VERSION 5.7 ;
  NOWIREEXTENSIONATPIN ON ;
  DIVIDERCHAR "/" ;
  BUSBITCHARS "[]" ;
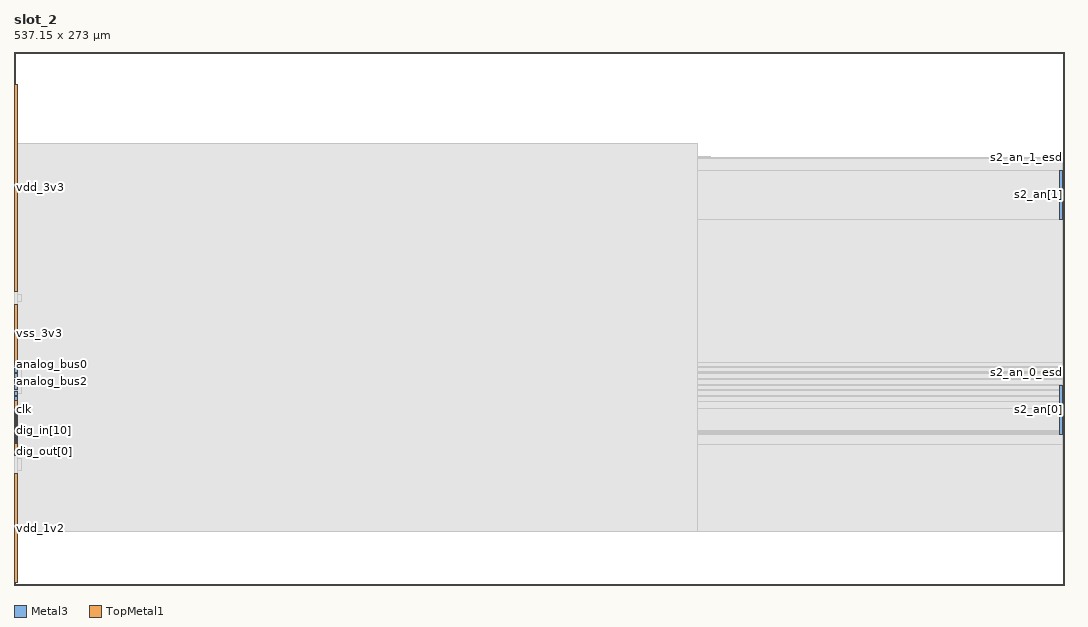
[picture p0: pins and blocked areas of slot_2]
MACRO slot_2
  CLASS BLOCK ;
  FOREIGN slot_2 ;
  ORIGIN 0.000 -0.010 ;
  SIZE 537.150 BY 273.000 ;
  PIN s2_an[0]
    ANTENNADIFFAREA 12.240000 ;
    PORT
      LAYER Metal3 ;
        RECT 535.050 77.160 536.440 101.930 ;
    END
  END s2_an[0]
  PIN s2_an[1]
    ANTENNADIFFAREA 12.240000 ;
    PORT
      LAYER Metal3 ;
        RECT 535.050 187.160 536.440 211.930 ;
    END
  END s2_an[1]
  PIN s2_an_0_esd
    PORT
      LAYER Metal3 ;
        RECT 535.150 108.415 537.150 108.905 ;
    END
  END s2_an_0_esd
  PIN s2_an_1_esd
    PORT
      LAYER Metal3 ;
        RECT 535.150 218.415 537.150 218.905 ;
    END
  END s2_an_1_esd
  PIN vbias
    PORT
      LAYER Metal3 ;
        RECT 0.000 94.215 2.000 96.215 ;
    END
  END vbias
  PIN dig_in[23]
    PORT
      LAYER Metal3 ;
        RECT 0.000 88.470 2.000 88.690 ;
    END
  END dig_in[23]
  PIN dig_in[22]
    PORT
      LAYER Metal3 ;
        RECT 0.000 88.030 2.000 88.250 ;
    END
  END dig_in[22]
  PIN dig_in[21]
    PORT
      LAYER Metal3 ;
        RECT 0.000 87.590 2.000 87.810 ;
    END
  END dig_in[21]
  PIN dig_in[20]
    PORT
      LAYER Metal3 ;
        RECT 0.000 87.150 2.000 87.370 ;
    END
  END dig_in[20]
  PIN dig_in[19]
    PORT
      LAYER Metal3 ;
        RECT 0.000 86.710 2.000 86.930 ;
    END
  END dig_in[19]
  PIN dig_in[18]
    PORT
      LAYER Metal3 ;
        RECT 0.000 86.270 2.000 86.490 ;
    END
  END dig_in[18]
  PIN dig_in[17]
    PORT
      LAYER Metal3 ;
        RECT 0.000 85.830 2.000 86.050 ;
    END
  END dig_in[17]
  PIN dig_in[16]
    PORT
      LAYER Metal3 ;
        RECT 0.000 85.390 2.000 85.610 ;
    END
  END dig_in[16]
  PIN dig_in[15]
    PORT
      LAYER Metal3 ;
        RECT 0.000 84.950 2.000 85.170 ;
    END
  END dig_in[15]
  PIN dig_in[14]
    PORT
      LAYER Metal3 ;
        RECT 0.000 84.510 2.000 84.730 ;
    END
  END dig_in[14]
  PIN dig_in[13]
    PORT
      LAYER Metal3 ;
        RECT 0.000 84.070 2.000 84.290 ;
    END
  END dig_in[13]
  PIN dig_in[12]
    PORT
      LAYER Metal3 ;
        RECT 0.000 83.630 2.000 83.850 ;
    END
  END dig_in[12]
  PIN dig_in[11]
    PORT
      LAYER Metal3 ;
        RECT 0.000 83.190 2.000 83.410 ;
    END
  END dig_in[11]
  PIN dig_in[10]
    PORT
      LAYER Metal3 ;
        RECT 0.000 82.750 2.000 82.970 ;
    END
  END dig_in[10]
  PIN dig_in[9]
    PORT
      LAYER Metal3 ;
        RECT 0.000 82.310 2.000 82.530 ;
    END
  END dig_in[9]
  PIN dig_in[8]
    PORT
      LAYER Metal3 ;
        RECT 0.000 81.870 2.000 82.090 ;
    END
  END dig_in[8]
  PIN dig_in[7]
    PORT
      LAYER Metal3 ;
        RECT 0.000 81.430 2.000 81.650 ;
    END
  END dig_in[7]
  PIN dig_in[6]
    PORT
      LAYER Metal3 ;
        RECT 0.000 80.990 2.000 81.210 ;
    END
  END dig_in[6]
  PIN dig_in[5]
    PORT
      LAYER Metal3 ;
        RECT 0.000 80.550 2.000 80.770 ;
    END
  END dig_in[5]
  PIN dig_in[4]
    PORT
      LAYER Metal3 ;
        RECT 0.000 80.110 2.000 80.330 ;
    END
  END dig_in[4]
  PIN dig_in[3]
    PORT
      LAYER Metal3 ;
        RECT 0.000 79.670 2.000 79.890 ;
    END
  END dig_in[3]
  PIN dig_in[2]
    PORT
      LAYER Metal3 ;
        RECT 0.000 79.230 2.000 79.450 ;
    END
  END dig_in[2]
  PIN dig_in[1]
    ANTENNAGATEAREA 0.260000 ;
    PORT
      LAYER Metal3 ;
        RECT 0.000 78.790 3.495 79.010 ;
    END
  END dig_in[1]
  PIN dig_in[0]
    ANTENNAGATEAREA 0.260000 ;
    PORT
      LAYER Metal3 ;
        RECT 0.000 78.350 4.085 78.570 ;
    END
  END dig_in[0]
  PIN dig_out[11]
    PORT
      LAYER Metal3 ;
        RECT 0.000 77.030 2.000 77.250 ;
    END
  END dig_out[11]
  PIN dig_out[10]
    PORT
      LAYER Metal3 ;
        RECT 0.000 76.590 2.000 76.810 ;
    END
  END dig_out[10]
  PIN dig_out[9]
    PORT
      LAYER Metal3 ;
        RECT 0.000 76.150 2.000 76.370 ;
    END
  END dig_out[9]
  PIN dig_out[8]
    PORT
      LAYER Metal3 ;
        RECT 0.000 75.710 2.000 75.930 ;
    END
  END dig_out[8]
  PIN dig_out[7]
    PORT
      LAYER Metal3 ;
        RECT 0.000 75.270 2.000 75.490 ;
    END
  END dig_out[7]
  PIN dig_out[6]
    PORT
      LAYER Metal3 ;
        RECT 0.000 74.830 2.000 75.050 ;
    END
  END dig_out[6]
  PIN dig_out[5]
    PORT
      LAYER Metal3 ;
        RECT 0.000 74.390 2.000 74.610 ;
    END
  END dig_out[5]
  PIN dig_out[4]
    PORT
      LAYER Metal3 ;
        RECT 0.000 73.950 2.000 74.170 ;
    END
  END dig_out[4]
  PIN dig_out[3]
    PORT
      LAYER Metal3 ;
        RECT 0.000 73.510 2.000 73.730 ;
    END
  END dig_out[3]
  PIN dig_out[2]
    PORT
      LAYER Metal3 ;
        RECT 0.000 73.070 2.000 73.290 ;
    END
  END dig_out[2]
  PIN dig_out[1]
    PORT
      LAYER Metal3 ;
        RECT 0.000 72.630 2.000 72.850 ;
    END
  END dig_out[1]
  PIN dig_out[0]
    PORT
      LAYER Metal3 ;
        RECT 0.000 72.190 2.000 72.410 ;
    END
  END dig_out[0]
  PIN ibias0
    PORT
      LAYER Metal3 ;
        RECT 0.000 97.155 2.000 99.155 ;
    END
  END ibias0
  PIN ibias1
    PORT
      LAYER Metal3 ;
        RECT 0.000 100.095 2.000 102.095 ;
    END
  END ibias1
  PIN analog_bus3
    PORT
      LAYER Metal3 ;
        RECT 0.000 103.035 2.000 105.035 ;
    END
  END analog_bus3
  PIN analog_bus2
    PORT
      LAYER Metal3 ;
        RECT 0.000 105.975 2.000 107.975 ;
    END
  END analog_bus2
  PIN analog_bus1
    PORT
      LAYER Metal3 ;
        RECT 0.000 108.915 2.000 110.915 ;
    END
  END analog_bus1
  PIN analog_bus0
    PORT
      LAYER Metal3 ;
        RECT 0.000 111.855 2.000 113.855 ;
    END
  END analog_bus0
  PIN enable
    PORT
      LAYER Metal3 ;
        RECT 0.000 89.360 2.000 89.580 ;
    END
  END enable
  PIN clk
    PORT
      LAYER Metal3 ;
        RECT 0.000 89.800 2.000 90.020 ;
    END
  END clk
  PIN reset
    PORT
      LAYER Metal3 ;
        RECT 0.000 88.910 2.000 89.130 ;
    END
  END reset
  PIN vss_1v2
    PORT
      LAYER TopMetal1 ;
        RECT 0.000 66.365 2.000 96.365 ;
    END
  END vss_1v2
  PIN vdd_1v2
    ANTENNAGATEAREA 0.520000 ;
    ANTENNADIFFAREA 19.559999 ;
    PORT
      LAYER TopMetal1 ;
        RECT 0.000 1.530 2.000 56.795 ;
    END
  END vdd_1v2
  PIN vss_3v3
    ANTENNAGATEAREA 1.520000 ;
    ANTENNADIFFAREA 288.532593 ;
    PORT
      LAYER TopMetal1 ;
        RECT 0.000 113.545 2.000 143.545 ;
    END
  END vss_3v3
  PIN vdd_3v3
    ANTENNAGATEAREA 3.000000 ;
    ANTENNADIFFAREA 209.860001 ;
    PORT
      LAYER TopMetal1 ;
        RECT 0.000 150.315 2.000 256.080 ;
    END
  END vdd_3v3
  OBS
      LAYER GatPoly ;
        RECT 261.855 70.105 356.120 218.985 ;
      LAYER Metal1 ;
        RECT 256.860 70.105 356.120 218.985 ;
      LAYER Metal2 ;
        RECT 3.935 70.410 400.360 218.680 ;
      LAYER Metal3 ;
        RECT 0.000 218.205 534.940 218.910 ;
        RECT 0.000 212.140 536.440 218.205 ;
        RECT 0.000 186.950 534.840 212.140 ;
        RECT 0.000 114.065 536.440 186.950 ;
        RECT 2.210 111.645 536.440 114.065 ;
        RECT 0.000 111.125 536.440 111.645 ;
        RECT 2.210 109.115 536.440 111.125 ;
        RECT 2.210 108.705 534.940 109.115 ;
        RECT 0.000 108.205 534.940 108.705 ;
        RECT 0.000 108.185 536.440 108.205 ;
        RECT 2.210 105.765 536.440 108.185 ;
        RECT 0.000 105.245 536.440 105.765 ;
        RECT 2.210 102.825 536.440 105.245 ;
        RECT 0.000 102.305 536.440 102.825 ;
        RECT 2.210 102.140 536.440 102.305 ;
        RECT 2.210 99.885 534.840 102.140 ;
        RECT 0.000 99.365 534.840 99.885 ;
        RECT 2.210 96.945 534.840 99.365 ;
        RECT 0.000 96.425 534.840 96.945 ;
        RECT 2.210 94.005 534.840 96.425 ;
        RECT 0.000 90.230 534.840 94.005 ;
        RECT 2.210 79.220 534.840 90.230 ;
        RECT 3.705 78.780 534.840 79.220 ;
        RECT 4.295 78.140 534.840 78.780 ;
        RECT 0.000 77.460 534.840 78.140 ;
        RECT 2.210 76.950 534.840 77.460 ;
        RECT 2.210 71.980 536.440 76.950 ;
        RECT 0.000 27.165 536.440 71.980 ;
      LAYER Metal4 ;
        RECT 2.000 27.165 349.665 225.760 ;
      LAYER TopMetal1 ;
        RECT 2.000 145.185 3.640 148.675 ;
        RECT 2.000 98.005 3.640 111.905 ;
        RECT 2.000 58.435 3.640 64.725 ;
  END
END slot_2
END LIBRARY

